VERSION 5.7 ;
  NOWIREEXTENSIONATPIN ON ;
  DIVIDERCHAR "/" ;
  BUSBITCHARS "[]" ;
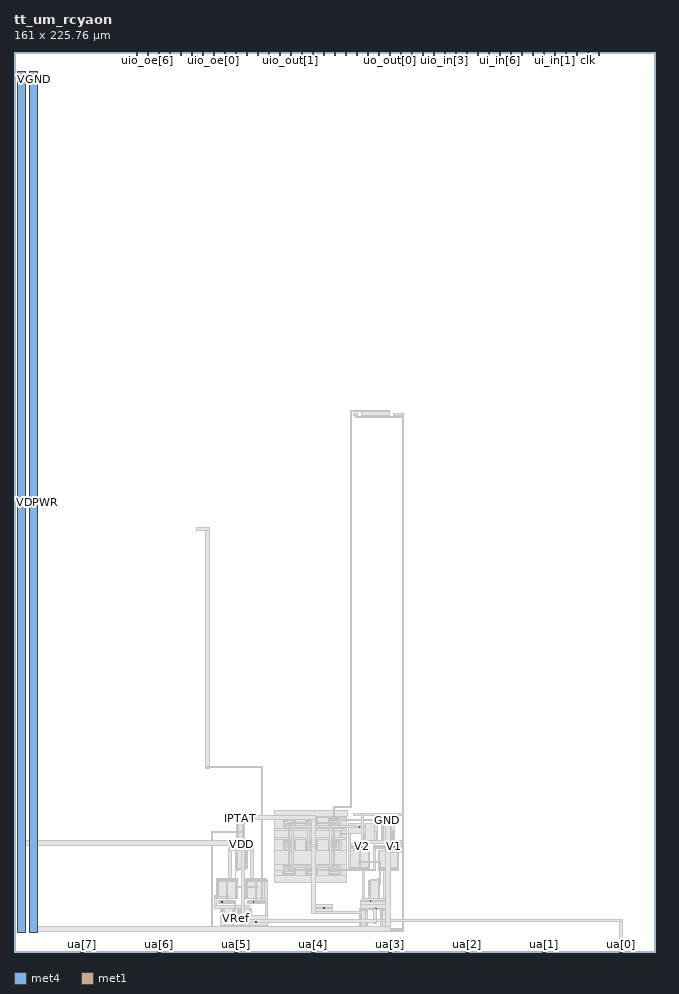
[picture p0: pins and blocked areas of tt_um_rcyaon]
MACRO tt_um_rcyaon
  CLASS BLOCK ;
  FOREIGN tt_um_rcyaon ;
  ORIGIN 0.000 0.000 ;
  SIZE 161.000 BY 225.760 ;
  PIN VGND
    USE GROUND ;
    PORT
      LAYER met4 ;
        RECT 4.000 5.000 6.000 220.760 ;
    END
  END VGND
  PIN VDPWR
    PORT
      LAYER met4 ;
        RECT 1.000 5.000 3.000 220.760 ;
    END
  END VDPWR
  PIN uo_out[7]
    PORT
      LAYER met4 ;
        RECT 74.830 224.760 75.130 225.760 ;
    END
  END uo_out[7]
  PIN uo_out[6]
    PORT
      LAYER met4 ;
        RECT 77.590 224.760 77.890 225.760 ;
    END
  END uo_out[6]
  PIN uo_out[5]
    PORT
      LAYER met4 ;
        RECT 80.350 224.760 80.650 225.760 ;
    END
  END uo_out[5]
  PIN uo_out[4]
    PORT
      LAYER met4 ;
        RECT 83.110 224.760 83.410 225.760 ;
    END
  END uo_out[4]
  PIN uo_out[3]
    PORT
      LAYER met4 ;
        RECT 85.870 224.760 86.170 225.760 ;
    END
  END uo_out[3]
  PIN uo_out[2]
    PORT
      LAYER met4 ;
        RECT 88.630 224.760 88.930 225.760 ;
    END
  END uo_out[2]
  PIN uo_out[1]
    PORT
      LAYER met4 ;
        RECT 91.390 224.760 91.690 225.760 ;
    END
  END uo_out[1]
  PIN uo_out[0]
    PORT
      LAYER met4 ;
        RECT 94.150 224.760 94.450 225.760 ;
    END
  END uo_out[0]
  PIN uio_out[7]
    PORT
      LAYER met4 ;
        RECT 52.750 224.760 53.050 225.760 ;
    END
  END uio_out[7]
  PIN uio_out[6]
    PORT
      LAYER met4 ;
        RECT 55.510 224.760 55.810 225.760 ;
    END
  END uio_out[6]
  PIN uio_out[5]
    PORT
      LAYER met4 ;
        RECT 58.270 224.760 58.570 225.760 ;
    END
  END uio_out[5]
  PIN uio_out[4]
    PORT
      LAYER met4 ;
        RECT 61.030 224.760 61.330 225.760 ;
    END
  END uio_out[4]
  PIN uio_out[3]
    PORT
      LAYER met4 ;
        RECT 63.790 224.760 64.090 225.760 ;
    END
  END uio_out[3]
  PIN uio_out[2]
    PORT
      LAYER met4 ;
        RECT 66.550 224.760 66.850 225.760 ;
    END
  END uio_out[2]
  PIN uio_out[1]
    PORT
      LAYER met4 ;
        RECT 69.310 224.760 69.610 225.760 ;
    END
  END uio_out[1]
  PIN uio_out[0]
    PORT
      LAYER met4 ;
        RECT 72.070 224.760 72.370 225.760 ;
    END
  END uio_out[0]
  PIN uio_oe[7]
    PORT
      LAYER met4 ;
        RECT 30.670 224.760 30.970 225.760 ;
    END
  END uio_oe[7]
  PIN uio_oe[6]
    PORT
      LAYER met4 ;
        RECT 33.430 224.760 33.730 225.760 ;
    END
  END uio_oe[6]
  PIN uio_oe[5]
    PORT
      LAYER met4 ;
        RECT 36.190 224.760 36.490 225.760 ;
    END
  END uio_oe[5]
  PIN uio_oe[4]
    PORT
      LAYER met4 ;
        RECT 38.950 224.760 39.250 225.760 ;
    END
  END uio_oe[4]
  PIN uio_oe[3]
    PORT
      LAYER met4 ;
        RECT 41.710 224.760 42.010 225.760 ;
    END
  END uio_oe[3]
  PIN uio_oe[2]
    PORT
      LAYER met4 ;
        RECT 44.470 224.760 44.770 225.760 ;
    END
  END uio_oe[2]
  PIN uio_oe[1]
    PORT
      LAYER met4 ;
        RECT 47.230 224.760 47.530 225.760 ;
    END
  END uio_oe[1]
  PIN uio_oe[0]
    PORT
      LAYER met4 ;
        RECT 49.990 224.760 50.290 225.760 ;
    END
  END uio_oe[0]
  PIN uio_in[7]
    PORT
      LAYER met4 ;
        RECT 96.910 224.760 97.210 225.760 ;
    END
  END uio_in[7]
  PIN uio_in[6]
    PORT
      LAYER met4 ;
        RECT 99.670 224.760 99.970 225.760 ;
    END
  END uio_in[6]
  PIN uio_in[5]
    PORT
      LAYER met4 ;
        RECT 102.430 224.760 102.730 225.760 ;
    END
  END uio_in[5]
  PIN uio_in[4]
    PORT
      LAYER met4 ;
        RECT 105.190 224.760 105.490 225.760 ;
    END
  END uio_in[4]
  PIN uio_in[3]
    PORT
      LAYER met4 ;
        RECT 107.950 224.760 108.250 225.760 ;
    END
  END uio_in[3]
  PIN uio_in[2]
    PORT
      LAYER met4 ;
        RECT 110.710 224.760 111.010 225.760 ;
    END
  END uio_in[2]
  PIN uio_in[1]
    PORT
      LAYER met4 ;
        RECT 113.470 224.760 113.770 225.760 ;
    END
  END uio_in[1]
  PIN uio_in[0]
    PORT
      LAYER met4 ;
        RECT 116.230 224.760 116.530 225.760 ;
    END
  END uio_in[0]
  PIN ui_in[7]
    PORT
      LAYER met4 ;
        RECT 118.990 224.760 119.290 225.760 ;
    END
  END ui_in[7]
  PIN ui_in[6]
    PORT
      LAYER met4 ;
        RECT 121.750 224.760 122.050 225.760 ;
    END
  END ui_in[6]
  PIN ui_in[5]
    PORT
      LAYER met4 ;
        RECT 124.510 224.760 124.810 225.760 ;
    END
  END ui_in[5]
  PIN ui_in[4]
    PORT
      LAYER met4 ;
        RECT 127.270 224.760 127.570 225.760 ;
    END
  END ui_in[4]
  PIN ui_in[3]
    PORT
      LAYER met4 ;
        RECT 130.030 224.760 130.330 225.760 ;
    END
  END ui_in[3]
  PIN ui_in[2]
    PORT
      LAYER met4 ;
        RECT 132.790 224.760 133.090 225.760 ;
    END
  END ui_in[2]
  PIN ui_in[1]
    PORT
      LAYER met4 ;
        RECT 135.550 224.760 135.850 225.760 ;
    END
  END ui_in[1]
  PIN ui_in[0]
    PORT
      LAYER met4 ;
        RECT 138.310 224.760 138.610 225.760 ;
    END
  END ui_in[0]
  PIN ua[7]
    PORT
      LAYER met4 ;
        RECT 16.570 0.000 17.470 1.000 ;
    END
  END ua[7]
  PIN ua[6]
    PORT
      LAYER met4 ;
        RECT 35.890 0.000 36.790 1.000 ;
    END
  END ua[6]
  PIN ua[5]
    PORT
      LAYER met4 ;
        RECT 55.210 0.000 56.110 1.000 ;
    END
  END ua[5]
  PIN ua[4]
    PORT
      LAYER met4 ;
        RECT 74.530 0.000 75.430 1.000 ;
    END
  END ua[4]
  PIN ua[3]
    PORT
      LAYER met4 ;
        RECT 93.850 0.000 94.750 1.000 ;
    END
  END ua[3]
  PIN ua[2]
    PORT
      LAYER met4 ;
        RECT 113.170 0.000 114.070 1.000 ;
    END
  END ua[2]
  PIN ua[1]
    PORT
      LAYER met4 ;
        RECT 132.490 0.000 133.390 1.000 ;
    END
  END ua[1]
  PIN ua[0]
    ANTENNAGATEAREA 16.000000 ;
    ANTENNADIFFAREA 3.180000 ;
    PORT
      LAYER met4 ;
        RECT 151.810 0.000 152.710 1.000 ;
    END
  END ua[0]
  PIN rst_n
    PORT
      LAYER met4 ;
        RECT 141.070 224.760 141.370 225.760 ;
    END
  END rst_n
  PIN ena
    PORT
      LAYER met4 ;
        RECT 146.590 224.760 146.890 225.760 ;
    END
  END ena
  PIN clk
    PORT
      LAYER met4 ;
        RECT 143.830 224.760 144.130 225.760 ;
    END
  END clk
  PIN IPTAT
    ANTENNAGATEAREA 4.000000 ;
    ANTENNADIFFAREA 1.522400 ;
    PORT
      LAYER met1 ;
        RECT 77.630 10.970 77.770 11.110 ;
    END
    PORT
      LAYER met1 ;
        RECT 56.745 33.310 56.885 33.450 ;
    END
  END IPTAT
  PIN GND
    ANTENNADIFFAREA 76.798798 ;
    PORT
      LAYER met1 ;
        RECT 93.515 32.945 93.655 33.085 ;
    END
    PORT
      LAYER met1 ;
        RECT 94.545 32.690 94.685 32.830 ;
    END
    PORT
      LAYER met1 ;
        RECT 53.980 5.875 54.120 6.015 ;
    END
    PORT
      LAYER met1 ;
        RECT 52.690 6.065 52.830 6.205 ;
    END
  END GND
  PIN VDD
    ANTENNADIFFAREA 13.678100 ;
    PORT
      LAYER met1 ;
        RECT 90.805 10.850 90.945 10.990 ;
    END
    PORT
      LAYER met1 ;
        RECT 89.390 12.765 89.505 12.860 ;
    END
    PORT
      LAYER met1 ;
        RECT 57.025 27.020 57.165 27.160 ;
    END
    PORT
      LAYER met1 ;
        RECT 57.870 26.035 57.985 26.130 ;
    END
  END VDD
  PIN V1
    ANTENNAGATEAREA 16.000000 ;
    ANTENNADIFFAREA 3.699200 ;
    PORT
      LAYER met1 ;
        RECT 95.125 26.315 95.355 26.560 ;
    END
    PORT
      LAYER met1 ;
        RECT 52.020 12.335 52.250 12.580 ;
    END
  END V1
  PIN V2
    ANTENNAGATEAREA 24.000000 ;
    ANTENNADIFFAREA 1.060000 ;
    PORT
      LAYER met1 ;
        RECT 87.185 26.310 87.325 26.450 ;
    END
    PORT
      LAYER met1 ;
        RECT 60.050 12.445 60.190 12.585 ;
    END
  END V2
  PIN Vout
    ANTENNAGATEAREA 54.022499 ;
    ANTENNADIFFAREA 6.561300 ;
    PORT
      LAYER met1 ;
        RECT 86.560 31.325 86.700 31.465 ;
    END
    PORT
      LAYER met1 ;
        RECT 60.675 7.430 60.815 7.570 ;
    END
  END Vout
  PIN VRef
    ANTENNAGATEAREA 16.000000 ;
    ANTENNADIFFAREA 3.180000 ;
    PORT
      LAYER met1 ;
        RECT 55.575 8.325 55.715 8.465 ;
    END
  END VRef
  OBS
      LAYER pwell ;
        RECT 65.675 34.245 66.355 34.795 ;
        RECT 67.510 34.350 82.215 35.315 ;
        RECT 67.510 34.245 83.340 34.350 ;
        RECT 65.675 33.485 83.340 34.245 ;
      LAYER nwell ;
        RECT 55.875 27.925 57.765 32.915 ;
      LAYER pwell ;
        RECT 65.675 31.035 67.845 33.485 ;
        RECT 70.295 31.035 73.385 33.485 ;
        RECT 75.835 31.035 79.050 33.485 ;
        RECT 81.500 31.035 83.340 33.485 ;
        RECT 65.675 30.275 83.340 31.035 ;
        RECT 65.675 28.745 66.355 30.275 ;
        RECT 67.470 28.745 83.340 30.275 ;
        RECT 65.675 27.985 83.340 28.745 ;
        RECT 87.895 28.015 91.245 32.275 ;
        RECT 92.205 28.015 95.555 32.275 ;
      LAYER nwell ;
        RECT 55.600 20.870 58.490 25.860 ;
      LAYER pwell ;
        RECT 65.675 25.535 67.845 27.985 ;
        RECT 70.295 25.535 73.370 27.985 ;
        RECT 75.820 25.535 79.050 27.985 ;
        RECT 81.500 25.535 83.340 27.985 ;
        RECT 65.675 25.080 83.340 25.535 ;
        RECT 65.675 24.775 71.055 25.080 ;
        RECT 65.675 22.635 66.355 24.775 ;
        RECT 67.470 23.995 71.055 24.775 ;
        RECT 72.610 23.995 76.580 25.080 ;
        RECT 78.290 23.995 83.340 25.080 ;
        RECT 67.470 23.315 83.340 23.995 ;
        RECT 67.470 22.635 71.055 23.315 ;
        RECT 65.675 22.345 71.055 22.635 ;
        RECT 72.625 22.345 76.595 23.315 ;
        RECT 78.290 22.345 83.340 23.315 ;
        RECT 65.675 21.875 83.340 22.345 ;
        RECT 65.675 19.425 67.845 21.875 ;
        RECT 70.295 19.425 73.385 21.875 ;
        RECT 75.835 19.425 79.050 21.875 ;
        RECT 81.500 19.425 83.340 21.875 ;
      LAYER nwell ;
        RECT 84.105 20.355 89.275 25.585 ;
        RECT 91.330 20.355 96.500 25.585 ;
      LAYER pwell ;
        RECT 65.675 19.030 83.340 19.425 ;
        RECT 67.085 18.665 83.340 19.030 ;
        RECT 67.510 18.585 83.340 18.665 ;
      LAYER nwell ;
        RECT 50.875 13.310 56.045 18.540 ;
        RECT 58.100 13.310 63.270 18.540 ;
      LAYER pwell ;
        RECT 67.510 17.655 82.215 18.585 ;
      LAYER nwell ;
        RECT 88.885 13.035 91.775 18.025 ;
      LAYER pwell ;
        RECT 51.820 6.620 55.170 10.880 ;
        RECT 56.130 6.620 59.480 10.880 ;
      LAYER nwell ;
        RECT 86.790 5.865 88.680 10.855 ;
        RECT 91.980 5.860 93.870 10.850 ;
      LAYER li1 ;
        RECT 85.365 134.910 86.055 134.960 ;
        RECT 87.345 134.910 88.035 134.960 ;
        RECT 89.340 134.910 90.030 134.960 ;
        RECT 91.380 134.910 92.070 134.960 ;
        RECT 93.390 134.910 94.080 134.960 ;
        RECT 95.365 134.930 96.055 134.960 ;
        RECT 95.345 134.910 96.055 134.930 ;
        RECT 85.265 134.740 86.155 134.910 ;
        RECT 87.245 134.740 88.135 134.910 ;
        RECT 89.240 134.740 90.130 134.910 ;
        RECT 91.280 134.740 92.170 134.910 ;
        RECT 93.290 134.740 94.180 134.910 ;
        RECT 95.265 134.740 96.155 134.910 ;
        RECT 85.365 134.660 86.055 134.740 ;
        RECT 87.345 134.660 88.035 134.740 ;
        RECT 89.340 134.660 90.030 134.740 ;
        RECT 91.380 134.660 92.070 134.740 ;
        RECT 93.390 134.660 94.080 134.740 ;
        RECT 95.345 134.660 96.055 134.740 ;
        RECT 85.675 134.565 85.845 134.660 ;
        RECT 87.520 134.620 87.690 134.660 ;
        RECT 89.620 134.620 89.790 134.660 ;
        RECT 91.620 134.620 91.790 134.660 ;
        RECT 93.620 134.620 93.790 134.660 ;
        RECT 95.345 134.600 95.515 134.660 ;
        RECT 46.305 106.285 46.475 106.295 ;
        RECT 45.925 106.235 46.615 106.285 ;
        RECT 45.825 106.065 46.715 106.235 ;
        RECT 45.925 105.985 46.615 106.065 ;
        RECT 46.305 105.965 46.475 105.985 ;
        RECT 48.475 46.355 48.645 46.435 ;
        RECT 48.210 46.305 48.900 46.355 ;
        RECT 48.110 46.135 49.000 46.305 ;
        RECT 48.210 46.055 48.900 46.135 ;
        RECT 67.640 34.810 67.810 35.140 ;
        RECT 68.440 34.810 68.610 35.140 ;
        RECT 69.250 34.810 69.420 35.140 ;
        RECT 70.260 34.810 70.430 35.140 ;
        RECT 71.060 34.810 71.230 35.140 ;
        RECT 71.870 34.810 72.040 35.140 ;
        RECT 72.665 34.810 72.835 35.140 ;
        RECT 73.465 34.810 73.635 35.140 ;
        RECT 74.275 34.810 74.445 35.140 ;
        RECT 75.075 34.810 75.245 35.140 ;
        RECT 75.875 34.810 76.045 35.140 ;
        RECT 76.675 34.810 76.845 35.140 ;
        RECT 77.590 34.810 77.760 35.140 ;
        RECT 78.715 34.810 78.885 35.140 ;
        RECT 79.515 34.810 79.685 35.140 ;
        RECT 80.315 34.810 80.485 35.140 ;
        RECT 81.115 34.810 81.285 35.140 ;
        RECT 81.915 34.810 82.085 35.140 ;
        RECT 85.365 34.740 86.055 34.820 ;
        RECT 87.345 34.740 88.035 34.820 ;
        RECT 89.340 34.740 90.030 34.820 ;
        RECT 91.380 34.740 92.070 34.820 ;
        RECT 93.390 34.740 94.080 34.820 ;
        RECT 95.365 34.740 96.055 34.820 ;
        RECT 65.850 34.495 66.180 34.665 ;
        RECT 85.265 34.570 86.155 34.740 ;
        RECT 87.245 34.570 88.135 34.740 ;
        RECT 89.240 34.570 90.130 34.740 ;
        RECT 91.280 34.570 92.170 34.740 ;
        RECT 93.290 34.570 94.180 34.740 ;
        RECT 95.265 34.570 96.155 34.740 ;
        RECT 85.365 34.520 86.055 34.570 ;
        RECT 87.345 34.520 88.035 34.570 ;
        RECT 89.340 34.520 90.030 34.570 ;
        RECT 91.380 34.520 92.070 34.570 ;
        RECT 93.390 34.520 94.080 34.570 ;
        RECT 95.365 34.520 96.055 34.570 ;
        RECT 85.540 34.355 85.710 34.520 ;
        RECT 87.365 34.250 87.535 34.520 ;
        RECT 89.580 34.345 89.750 34.520 ;
        RECT 91.670 34.350 91.840 34.520 ;
        RECT 93.600 34.350 93.770 34.520 ;
        RECT 95.635 34.320 95.805 34.520 ;
        RECT 65.850 33.695 66.180 33.865 ;
        RECT 67.215 33.615 68.205 34.115 ;
        RECT 69.935 33.615 70.925 34.115 ;
        RECT 71.640 33.845 71.970 34.015 ;
        RECT 56.320 32.945 57.320 33.175 ;
        RECT 65.850 32.895 66.180 33.065 ;
        RECT 56.095 28.735 56.265 32.735 ;
        RECT 57.375 28.735 57.545 32.735 ;
        RECT 65.850 32.075 66.180 32.245 ;
        RECT 65.850 31.275 66.180 31.445 ;
        RECT 67.215 30.905 67.715 33.615 ;
        RECT 68.025 31.575 68.385 33.305 ;
        RECT 68.730 31.920 69.410 32.600 ;
        RECT 69.755 31.575 70.115 33.305 ;
        RECT 68.025 31.215 70.115 31.575 ;
        RECT 70.425 30.905 70.925 33.615 ;
        RECT 72.755 33.615 73.745 34.115 ;
        RECT 75.475 33.615 76.465 34.115 ;
        RECT 77.250 33.845 77.580 34.015 ;
        RECT 71.640 33.000 71.970 33.170 ;
        RECT 71.640 32.200 71.970 32.370 ;
        RECT 71.640 31.400 71.970 31.570 ;
        RECT 65.850 30.475 66.180 30.645 ;
        RECT 67.215 30.405 68.205 30.905 ;
        RECT 69.935 30.405 70.925 30.905 ;
        RECT 72.755 30.905 73.255 33.615 ;
        RECT 73.565 31.575 73.925 33.305 ;
        RECT 74.270 31.920 74.950 32.600 ;
        RECT 75.295 31.575 75.655 33.305 ;
        RECT 73.565 31.215 75.655 31.575 ;
        RECT 75.965 30.905 76.465 33.615 ;
        RECT 78.420 33.615 79.410 34.115 ;
        RECT 81.140 33.615 82.130 34.115 ;
        RECT 82.835 34.050 83.165 34.220 ;
        RECT 77.250 33.000 77.580 33.170 ;
        RECT 77.250 32.200 77.580 32.370 ;
        RECT 77.250 31.400 77.580 31.570 ;
        RECT 71.640 30.600 71.970 30.770 ;
        RECT 72.755 30.405 73.745 30.905 ;
        RECT 75.475 30.405 76.465 30.905 ;
        RECT 78.420 30.905 78.920 33.615 ;
        RECT 79.230 31.575 79.590 33.305 ;
        RECT 79.935 31.920 80.615 32.600 ;
        RECT 80.960 31.575 81.320 33.305 ;
        RECT 79.230 31.215 81.320 31.575 ;
        RECT 81.630 30.905 82.130 33.615 ;
        RECT 82.835 33.250 83.165 33.420 ;
        RECT 82.835 32.450 83.165 32.620 ;
        RECT 82.835 31.630 83.165 31.800 ;
        RECT 77.250 30.600 77.580 30.770 ;
        RECT 78.420 30.405 79.410 30.905 ;
        RECT 81.140 30.405 82.130 30.905 ;
        RECT 82.835 30.830 83.165 31.000 ;
        RECT 82.835 29.965 83.165 30.135 ;
        RECT 65.850 29.625 66.180 29.795 ;
        RECT 67.600 29.425 67.770 29.755 ;
        RECT 68.420 29.425 68.590 29.755 ;
        RECT 69.220 29.425 69.390 29.755 ;
        RECT 70.020 29.425 70.190 29.755 ;
        RECT 70.840 29.425 71.010 29.755 ;
        RECT 71.800 29.425 71.970 29.755 ;
        RECT 72.665 29.425 72.835 29.755 ;
        RECT 73.465 29.425 73.635 29.755 ;
        RECT 74.275 29.425 74.445 29.755 ;
        RECT 75.075 29.425 75.245 29.755 ;
        RECT 75.875 29.425 76.045 29.755 ;
        RECT 76.675 29.425 76.845 29.755 ;
        RECT 77.590 29.425 77.760 29.755 ;
        RECT 78.715 29.425 78.885 29.755 ;
        RECT 79.515 29.425 79.685 29.755 ;
        RECT 80.315 29.425 80.485 29.755 ;
        RECT 81.115 29.425 81.285 29.755 ;
        RECT 81.915 29.425 82.085 29.755 ;
        RECT 82.835 29.090 83.165 29.260 ;
        RECT 65.850 28.735 66.180 28.905 ;
        RECT 56.065 28.115 57.575 28.385 ;
        RECT 67.215 28.115 68.205 28.615 ;
        RECT 69.935 28.115 70.925 28.615 ;
        RECT 71.640 28.455 71.970 28.625 ;
        RECT 65.850 27.925 66.180 28.095 ;
        RECT 65.850 27.125 66.180 27.295 ;
        RECT 65.850 26.325 66.180 26.495 ;
        RECT 55.790 25.400 58.300 25.670 ;
        RECT 65.850 25.525 66.180 25.695 ;
        RECT 67.215 25.405 67.715 28.115 ;
        RECT 68.025 26.075 68.385 27.805 ;
        RECT 68.730 26.420 69.410 27.100 ;
        RECT 69.755 26.075 70.115 27.805 ;
        RECT 68.025 25.715 70.115 26.075 ;
        RECT 70.425 25.405 70.925 28.115 ;
        RECT 72.740 28.115 73.730 28.615 ;
        RECT 75.460 28.115 76.450 28.615 ;
        RECT 77.195 28.455 77.525 28.625 ;
        RECT 71.640 27.610 71.970 27.780 ;
        RECT 71.640 26.810 71.970 26.980 ;
        RECT 71.640 26.010 71.970 26.180 ;
        RECT 55.820 21.050 55.990 25.050 ;
        RECT 58.100 21.050 58.270 25.050 ;
        RECT 67.215 24.905 68.205 25.405 ;
        RECT 69.935 24.905 70.925 25.405 ;
        RECT 72.740 25.405 73.240 28.115 ;
        RECT 73.550 26.075 73.910 27.805 ;
        RECT 74.255 26.420 74.935 27.100 ;
        RECT 75.280 26.075 75.640 27.805 ;
        RECT 73.550 25.715 75.640 26.075 ;
        RECT 75.950 25.405 76.450 28.115 ;
        RECT 78.420 28.115 79.410 28.615 ;
        RECT 81.140 28.115 82.130 28.615 ;
        RECT 82.835 28.290 83.165 28.460 ;
        RECT 88.065 28.145 88.235 32.145 ;
        RECT 90.345 28.145 90.515 32.145 ;
        RECT 90.835 28.145 91.105 32.145 ;
        RECT 92.375 28.145 92.545 32.145 ;
        RECT 94.655 28.145 94.825 32.145 ;
        RECT 95.145 28.145 95.415 32.145 ;
        RECT 77.195 27.610 77.525 27.780 ;
        RECT 77.195 26.810 77.525 26.980 ;
        RECT 77.195 26.010 77.525 26.180 ;
        RECT 71.640 25.210 71.970 25.380 ;
        RECT 72.740 24.905 73.730 25.405 ;
        RECT 75.460 24.905 76.450 25.405 ;
        RECT 78.420 25.405 78.920 28.115 ;
        RECT 79.230 26.075 79.590 27.805 ;
        RECT 79.935 26.420 80.615 27.100 ;
        RECT 80.960 26.075 81.320 27.805 ;
        RECT 79.230 25.715 81.320 26.075 ;
        RECT 81.630 25.405 82.130 28.115 ;
        RECT 88.290 27.705 90.290 27.935 ;
        RECT 92.600 27.705 94.600 27.935 ;
        RECT 82.835 27.480 83.165 27.650 ;
        RECT 82.835 26.680 83.165 26.850 ;
        RECT 82.835 25.880 83.165 26.050 ;
        RECT 84.550 26.015 88.830 26.245 ;
        RECT 91.775 26.015 96.055 26.245 ;
        RECT 77.195 25.210 77.525 25.380 ;
        RECT 78.420 24.905 79.410 25.405 ;
        RECT 81.140 24.905 82.130 25.405 ;
        RECT 82.835 25.080 83.165 25.250 ;
        RECT 65.850 24.715 66.180 24.885 ;
        RECT 82.835 24.270 83.165 24.440 ;
        RECT 65.850 23.985 66.180 24.155 ;
        RECT 67.600 23.490 67.770 23.820 ;
        RECT 68.420 23.490 68.590 23.820 ;
        RECT 69.220 23.490 69.390 23.820 ;
        RECT 70.020 23.490 70.190 23.820 ;
        RECT 70.840 23.490 71.010 23.820 ;
        RECT 71.800 23.490 71.970 23.820 ;
        RECT 72.665 23.490 72.835 23.820 ;
        RECT 73.465 23.490 73.635 23.820 ;
        RECT 74.275 23.490 74.445 23.820 ;
        RECT 75.075 23.490 75.245 23.820 ;
        RECT 75.875 23.490 76.045 23.820 ;
        RECT 76.675 23.490 76.845 23.820 ;
        RECT 77.590 23.490 77.760 23.820 ;
        RECT 78.715 23.490 78.885 23.820 ;
        RECT 79.515 23.490 79.685 23.820 ;
        RECT 80.315 23.490 80.485 23.820 ;
        RECT 81.115 23.490 81.285 23.820 ;
        RECT 81.915 23.490 82.085 23.820 ;
        RECT 82.835 23.305 83.165 23.475 ;
        RECT 65.850 23.065 66.180 23.235 ;
        RECT 82.835 22.600 83.165 22.770 ;
        RECT 65.850 22.360 66.180 22.530 ;
        RECT 67.215 22.005 68.205 22.505 ;
        RECT 69.935 22.005 70.925 22.505 ;
        RECT 71.635 22.045 71.965 22.215 ;
        RECT 65.850 21.560 66.180 21.730 ;
        RECT 56.045 20.610 58.045 20.840 ;
        RECT 65.850 20.760 66.180 20.930 ;
        RECT 65.850 19.960 66.180 20.130 ;
        RECT 65.850 19.160 66.180 19.330 ;
        RECT 67.215 19.295 67.715 22.005 ;
        RECT 68.025 19.965 68.385 21.695 ;
        RECT 68.730 20.310 69.410 20.990 ;
        RECT 69.755 19.965 70.115 21.695 ;
        RECT 68.025 19.605 70.115 19.965 ;
        RECT 70.425 19.295 70.925 22.005 ;
        RECT 72.755 22.005 73.745 22.505 ;
        RECT 75.475 22.005 76.465 22.505 ;
        RECT 77.195 22.045 77.525 22.215 ;
        RECT 71.635 21.245 71.965 21.415 ;
        RECT 71.635 20.445 71.965 20.615 ;
        RECT 71.635 19.645 71.965 19.815 ;
        RECT 67.215 18.795 68.205 19.295 ;
        RECT 69.935 18.795 70.925 19.295 ;
        RECT 72.755 19.295 73.255 22.005 ;
        RECT 73.565 19.965 73.925 21.695 ;
        RECT 74.270 20.310 74.950 20.990 ;
        RECT 75.295 19.965 75.655 21.695 ;
        RECT 73.565 19.605 75.655 19.965 ;
        RECT 75.965 19.295 76.465 22.005 ;
        RECT 78.420 22.005 79.410 22.505 ;
        RECT 81.140 22.005 82.130 22.505 ;
        RECT 77.195 21.245 77.525 21.415 ;
        RECT 77.195 20.445 77.525 20.615 ;
        RECT 77.195 19.645 77.525 19.815 ;
        RECT 71.635 18.845 71.965 19.015 ;
        RECT 72.755 18.795 73.745 19.295 ;
        RECT 75.475 18.795 76.465 19.295 ;
        RECT 78.420 19.295 78.920 22.005 ;
        RECT 79.230 19.965 79.590 21.695 ;
        RECT 79.935 20.310 80.615 20.990 ;
        RECT 80.960 19.965 81.320 21.695 ;
        RECT 79.230 19.605 81.320 19.965 ;
        RECT 81.630 19.295 82.130 22.005 ;
        RECT 82.835 21.915 83.165 22.085 ;
        RECT 84.325 21.405 84.495 25.405 ;
        RECT 86.605 21.405 86.775 25.405 ;
        RECT 88.885 21.405 89.055 25.405 ;
        RECT 91.550 21.405 91.720 25.405 ;
        RECT 93.830 21.405 94.000 25.405 ;
        RECT 96.110 21.405 96.280 25.405 ;
        RECT 82.835 21.115 83.165 21.285 ;
        RECT 84.295 20.545 89.085 20.815 ;
        RECT 91.520 20.545 96.310 20.815 ;
        RECT 82.835 20.315 83.165 20.485 ;
        RECT 82.835 19.515 83.165 19.685 ;
        RECT 77.195 18.845 77.525 19.015 ;
        RECT 78.420 18.795 79.410 19.295 ;
        RECT 81.140 18.795 82.130 19.295 ;
        RECT 82.835 18.715 83.165 18.885 ;
        RECT 51.065 18.080 55.855 18.350 ;
        RECT 58.290 18.080 63.080 18.350 ;
        RECT 67.640 17.830 67.810 18.160 ;
        RECT 68.440 17.830 68.610 18.160 ;
        RECT 69.250 17.830 69.420 18.160 ;
        RECT 70.260 17.830 70.430 18.160 ;
        RECT 71.060 17.830 71.230 18.160 ;
        RECT 71.870 17.830 72.040 18.160 ;
        RECT 72.665 17.830 72.835 18.160 ;
        RECT 73.465 17.830 73.635 18.160 ;
        RECT 74.275 17.830 74.445 18.160 ;
        RECT 75.075 17.830 75.245 18.160 ;
        RECT 75.875 17.830 76.045 18.160 ;
        RECT 76.675 17.830 76.845 18.160 ;
        RECT 77.590 17.830 77.760 18.160 ;
        RECT 78.715 17.830 78.885 18.160 ;
        RECT 79.515 17.830 79.685 18.160 ;
        RECT 80.315 17.830 80.485 18.160 ;
        RECT 81.115 17.830 81.285 18.160 ;
        RECT 81.915 17.830 82.085 18.160 ;
        RECT 89.330 18.055 91.330 18.285 ;
        RECT 51.095 13.490 51.265 17.490 ;
        RECT 53.375 13.490 53.545 17.490 ;
        RECT 55.655 13.490 55.825 17.490 ;
        RECT 58.320 13.490 58.490 17.490 ;
        RECT 60.600 13.490 60.770 17.490 ;
        RECT 62.880 13.490 63.050 17.490 ;
        RECT 89.105 13.845 89.275 17.845 ;
        RECT 91.385 13.845 91.555 17.845 ;
        RECT 89.075 13.225 91.585 13.495 ;
        RECT 51.320 12.650 55.600 12.880 ;
        RECT 58.545 12.650 62.825 12.880 ;
        RECT 52.775 10.960 54.775 11.190 ;
        RECT 57.085 10.960 59.085 11.190 ;
        RECT 51.960 6.750 52.230 10.750 ;
        RECT 52.550 6.750 52.720 10.750 ;
        RECT 54.830 6.750 55.000 10.750 ;
        RECT 56.270 6.750 56.540 10.750 ;
        RECT 56.860 6.750 57.030 10.750 ;
        RECT 59.140 6.750 59.310 10.750 ;
        RECT 86.980 10.395 88.490 10.665 ;
        RECT 92.170 10.390 93.680 10.660 ;
        RECT 45.925 6.065 46.615 6.145 ;
        RECT 48.210 6.135 48.900 6.215 ;
        RECT 45.825 5.895 46.715 6.065 ;
        RECT 48.110 5.965 49.000 6.135 ;
        RECT 87.010 6.045 87.180 10.045 ;
        RECT 88.290 6.045 88.460 10.045 ;
        RECT 92.200 6.040 92.370 10.040 ;
        RECT 93.480 6.040 93.650 10.040 ;
        RECT 48.210 5.915 48.900 5.965 ;
        RECT 45.925 5.845 46.615 5.895 ;
        RECT 46.425 5.775 46.595 5.845 ;
        RECT 48.690 5.750 48.860 5.915 ;
        RECT 87.235 5.605 88.235 5.835 ;
        RECT 92.425 5.600 93.425 5.830 ;
      LAYER met1 ;
        RECT 84.405 135.645 94.245 135.895 ;
        RECT 48.000 106.490 49.090 106.500 ;
        RECT 45.740 105.725 49.090 106.490 ;
        RECT 48.000 46.590 49.090 105.725 ;
        RECT 48.000 46.190 62.365 46.590 ;
        RECT 48.000 46.060 49.090 46.190 ;
        RECT 84.410 36.595 84.660 135.645 ;
        RECT 85.200 134.490 86.285 135.025 ;
        RECT 87.120 134.485 94.245 135.645 ;
        RECT 95.165 134.545 97.605 135.160 ;
        RECT 97.400 134.280 97.605 134.545 ;
        RECT 97.390 133.960 97.650 134.280 ;
        RECT 80.250 36.265 84.660 36.595 ;
        RECT 80.285 36.195 80.545 36.265 ;
        RECT 84.410 36.235 84.660 36.265 ;
        RECT 55.850 33.450 57.770 34.040 ;
        RECT 55.850 33.310 56.745 33.450 ;
        RECT 56.885 33.310 57.770 33.450 ;
        RECT 55.850 32.920 57.770 33.310 ;
        RECT 65.320 34.035 83.540 35.540 ;
        RECT 97.400 34.690 97.605 133.960 ;
        RECT 85.195 34.190 97.630 34.690 ;
        RECT 65.320 33.615 83.530 34.035 ;
        RECT 65.320 33.175 67.260 33.615 ;
        RECT 1.855 27.205 2.115 27.525 ;
        RECT 45.745 5.375 46.810 6.195 ;
        RECT 49.550 6.170 49.840 30.295 ;
        RECT 56.065 28.735 56.295 32.735 ;
        RECT 57.345 30.430 57.575 32.735 ;
        RECT 65.320 30.905 67.725 33.175 ;
        RECT 68.025 32.945 70.115 33.305 ;
        RECT 68.025 31.735 68.555 32.945 ;
        RECT 68.730 31.920 69.410 32.600 ;
        RECT 69.585 31.735 70.115 32.945 ;
        RECT 68.020 31.215 70.115 31.735 ;
        RECT 70.490 30.905 73.135 33.615 ;
        RECT 73.565 32.945 75.655 33.305 ;
        RECT 73.565 31.735 74.095 32.945 ;
        RECT 74.270 31.920 74.950 32.600 ;
        RECT 75.125 31.735 75.655 32.945 ;
        RECT 73.555 31.215 75.655 31.735 ;
        RECT 76.020 30.905 78.840 33.615 ;
        RECT 79.225 32.945 81.320 33.305 ;
        RECT 79.225 31.735 79.755 32.945 ;
        RECT 79.935 31.920 80.615 32.600 ;
        RECT 80.790 31.735 81.320 32.945 ;
        RECT 79.225 31.205 81.320 31.735 ;
        RECT 82.030 33.165 83.530 33.615 ;
        RECT 90.370 33.165 95.570 33.275 ;
        RECT 82.030 33.085 95.570 33.165 ;
        RECT 82.030 32.945 93.515 33.085 ;
        RECT 93.655 32.945 95.570 33.085 ;
        RECT 82.030 32.910 95.570 32.945 ;
        RECT 82.030 30.905 83.530 32.910 ;
        RECT 90.370 32.830 95.570 32.910 ;
        RECT 90.370 32.690 94.545 32.830 ;
        RECT 94.685 32.690 95.570 32.830 ;
        RECT 90.370 32.355 95.570 32.690 ;
        RECT 57.345 30.300 57.730 30.430 ;
        RECT 65.320 30.405 83.530 30.905 ;
        RECT 57.345 29.980 57.770 30.300 ;
        RECT 57.345 29.745 57.730 29.980 ;
        RECT 57.345 28.735 57.575 29.745 ;
        RECT 56.095 28.505 56.295 28.735 ;
        RECT 65.320 28.615 81.730 30.405 ;
        RECT 82.030 29.735 83.530 30.405 ;
        RECT 81.885 29.445 83.530 29.735 ;
        RECT 82.030 28.615 83.530 29.445 ;
        RECT 55.865 27.160 57.765 28.505 ;
        RECT 55.865 27.020 57.025 27.160 ;
        RECT 57.165 27.020 57.765 27.160 ;
        RECT 55.865 26.315 57.765 27.020 ;
        RECT 65.320 28.115 83.530 28.615 ;
        RECT 53.930 26.130 60.020 26.315 ;
        RECT 53.930 26.035 57.870 26.130 ;
        RECT 57.985 26.035 60.020 26.130 ;
        RECT 53.930 25.400 60.020 26.035 ;
        RECT 65.320 25.410 67.725 28.115 ;
        RECT 68.025 27.445 70.115 27.805 ;
        RECT 68.025 26.230 68.555 27.445 ;
        RECT 68.730 26.420 69.410 27.100 ;
        RECT 69.585 26.230 70.115 27.445 ;
        RECT 68.020 25.710 70.115 26.230 ;
        RECT 70.490 25.410 73.135 28.115 ;
        RECT 73.545 27.445 75.640 27.805 ;
        RECT 73.545 26.230 74.075 27.445 ;
        RECT 74.255 26.420 74.935 27.100 ;
        RECT 75.110 26.230 75.640 27.445 ;
        RECT 73.545 25.715 75.650 26.230 ;
        RECT 73.555 25.710 75.650 25.715 ;
        RECT 76.020 25.410 78.840 28.115 ;
        RECT 79.230 27.445 81.320 27.805 ;
        RECT 79.230 26.230 79.760 27.445 ;
        RECT 79.935 26.420 80.615 27.100 ;
        RECT 80.790 26.230 81.320 27.445 ;
        RECT 79.225 25.710 81.320 26.230 ;
        RECT 82.030 25.410 83.530 28.115 ;
        RECT 53.930 18.350 54.595 25.400 ;
        RECT 55.865 25.345 57.765 25.400 ;
        RECT 55.790 21.970 56.020 25.050 ;
        RECT 58.060 24.820 58.335 25.400 ;
        RECT 55.445 21.050 56.020 21.970 ;
        RECT 58.070 21.050 58.300 24.820 ;
        RECT 55.445 20.880 55.990 21.050 ;
        RECT 55.445 20.860 56.290 20.880 ;
        RECT 55.445 20.590 58.045 20.860 ;
        RECT 55.445 20.545 56.290 20.590 ;
        RECT 59.330 18.350 59.995 25.400 ;
        RECT 65.320 22.005 83.530 25.410 ;
        RECT 65.320 20.355 67.725 22.005 ;
        RECT 68.025 21.335 70.115 21.695 ;
        RECT 65.320 19.295 67.260 20.355 ;
        RECT 68.025 20.125 68.555 21.335 ;
        RECT 68.730 20.310 69.410 20.990 ;
        RECT 69.585 20.125 70.115 21.335 ;
        RECT 68.020 19.605 70.115 20.125 ;
        RECT 70.490 19.295 73.135 22.005 ;
        RECT 73.565 21.335 75.655 21.695 ;
        RECT 73.565 20.125 74.095 21.335 ;
        RECT 74.270 20.310 74.950 20.990 ;
        RECT 75.125 20.125 75.655 21.335 ;
        RECT 73.555 19.605 75.655 20.125 ;
        RECT 76.020 19.295 78.840 22.005 ;
        RECT 79.230 21.335 81.325 21.695 ;
        RECT 79.230 20.125 79.760 21.335 ;
        RECT 79.935 20.310 80.615 20.990 ;
        RECT 80.795 20.125 81.325 21.335 ;
        RECT 79.225 19.605 81.325 20.125 ;
        RECT 82.030 19.295 83.530 22.005 ;
        RECT 83.815 32.145 88.195 32.275 ;
        RECT 90.370 32.145 91.235 32.355 ;
        RECT 94.670 32.145 95.570 32.355 ;
        RECT 83.815 31.465 88.265 32.145 ;
        RECT 83.815 31.325 86.560 31.465 ;
        RECT 86.700 31.325 88.265 31.465 ;
        RECT 83.815 29.760 88.265 31.325 ;
        RECT 83.815 25.405 84.390 29.760 ;
        RECT 88.035 28.145 88.265 29.760 ;
        RECT 90.315 30.270 91.235 32.145 ;
        RECT 90.315 28.145 90.545 30.270 ;
        RECT 90.835 28.145 91.105 30.270 ;
        RECT 92.345 29.965 92.575 32.145 ;
        RECT 94.625 30.410 95.570 32.145 ;
        RECT 92.330 27.955 92.615 29.965 ;
        RECT 94.625 28.145 94.855 30.410 ;
        RECT 95.145 28.145 95.415 30.410 ;
        RECT 88.290 27.950 90.290 27.955 ;
        RECT 92.330 27.950 94.600 27.955 ;
        RECT 88.280 27.280 97.205 27.950 ;
        RECT 84.585 26.665 88.795 27.105 ;
        RECT 84.570 26.450 88.810 26.665 ;
        RECT 91.805 26.655 96.045 26.665 ;
        RECT 84.570 26.310 87.185 26.450 ;
        RECT 87.325 26.310 88.810 26.450 ;
        RECT 84.570 26.265 88.810 26.310 ;
        RECT 90.210 26.560 96.045 26.655 ;
        RECT 90.210 26.315 95.125 26.560 ;
        RECT 95.355 26.315 96.045 26.560 ;
        RECT 90.210 26.265 96.045 26.315 ;
        RECT 84.550 25.995 88.830 26.265 ;
        RECT 90.210 26.070 96.055 26.265 ;
        RECT 83.815 21.235 84.525 25.405 ;
        RECT 86.575 22.740 86.805 25.805 ;
        RECT 86.395 22.380 86.970 22.740 ;
        RECT 86.575 21.405 86.805 22.380 ;
        RECT 88.855 21.235 89.085 25.405 ;
        RECT 83.815 21.055 89.085 21.235 ;
        RECT 84.295 21.005 89.085 21.055 ;
        RECT 84.295 20.545 89.085 20.815 ;
        RECT 51.065 18.080 55.855 18.350 ;
        RECT 58.290 18.080 63.080 18.350 ;
        RECT 51.065 17.660 55.855 17.890 ;
        RECT 50.170 11.615 50.815 14.050 ;
        RECT 51.065 13.490 51.295 17.660 ;
        RECT 53.345 14.260 53.575 17.490 ;
        RECT 55.625 16.515 55.855 17.660 ;
        RECT 58.290 17.840 63.080 17.890 ;
        RECT 58.290 17.660 63.560 17.840 ;
        RECT 55.440 16.155 56.015 16.515 ;
        RECT 53.185 13.665 53.760 14.260 ;
        RECT 53.345 13.090 53.575 13.665 ;
        RECT 55.625 13.490 55.855 16.155 ;
        RECT 58.290 13.490 58.520 17.660 ;
        RECT 60.570 16.515 60.800 17.490 ;
        RECT 60.405 16.155 60.980 16.515 ;
        RECT 60.570 13.090 60.800 16.155 ;
        RECT 62.850 13.490 63.560 17.660 ;
        RECT 65.320 17.415 83.530 19.295 ;
        RECT 65.320 17.405 67.260 17.415 ;
        RECT 82.030 17.395 83.530 17.415 ;
        RECT 87.380 13.495 88.045 20.545 ;
        RECT 90.210 20.475 90.575 26.070 ;
        RECT 91.775 25.995 96.055 26.070 ;
        RECT 91.520 22.740 91.750 25.405 ;
        RECT 93.800 25.230 94.030 25.805 ;
        RECT 93.615 24.635 94.190 25.230 ;
        RECT 91.360 22.380 91.935 22.740 ;
        RECT 91.520 21.235 91.750 22.380 ;
        RECT 93.800 21.405 94.030 24.635 ;
        RECT 96.080 21.235 96.310 25.405 ;
        RECT 96.560 24.845 97.205 27.280 ;
        RECT 91.520 21.005 96.310 21.235 ;
        RECT 91.520 20.545 96.310 20.815 ;
        RECT 91.085 18.305 91.930 18.350 ;
        RECT 89.330 18.035 91.930 18.305 ;
        RECT 91.085 18.015 91.930 18.035 ;
        RECT 91.385 17.845 91.930 18.015 ;
        RECT 89.075 14.075 89.305 17.845 ;
        RECT 91.355 16.925 91.930 17.845 ;
        RECT 89.040 13.495 89.315 14.075 ;
        RECT 91.355 13.845 91.585 16.925 ;
        RECT 92.780 13.495 93.445 20.545 ;
        RECT 51.320 12.630 55.600 12.900 ;
        RECT 58.545 12.630 62.825 12.900 ;
        RECT 51.330 12.580 55.570 12.630 ;
        RECT 51.330 12.335 52.020 12.580 ;
        RECT 52.250 12.335 55.570 12.580 ;
        RECT 51.330 12.230 55.570 12.335 ;
        RECT 58.565 12.585 62.805 12.630 ;
        RECT 58.565 12.445 60.050 12.585 ;
        RECT 60.190 12.445 62.805 12.585 ;
        RECT 58.565 12.230 62.805 12.445 ;
        RECT 50.170 10.945 59.095 11.615 ;
        RECT 52.775 10.940 55.045 10.945 ;
        RECT 57.085 10.940 59.085 10.945 ;
        RECT 51.960 8.485 52.230 10.750 ;
        RECT 52.520 8.485 52.750 10.750 ;
        RECT 54.760 8.930 55.045 10.940 ;
        RECT 48.005 5.720 49.840 6.170 ;
        RECT 51.805 6.750 52.750 8.485 ;
        RECT 54.800 6.750 55.030 8.930 ;
        RECT 55.350 8.465 55.890 9.130 ;
        RECT 56.270 8.625 56.540 10.750 ;
        RECT 56.830 8.625 57.060 10.750 ;
        RECT 55.350 8.325 55.575 8.465 ;
        RECT 55.715 8.325 55.890 8.465 ;
        RECT 55.350 7.445 55.890 8.325 ;
        RECT 56.140 6.750 57.060 8.625 ;
        RECT 59.110 9.135 59.340 10.750 ;
        RECT 62.985 9.135 63.560 13.490 ;
        RECT 87.355 12.910 93.445 13.495 ;
        RECT 86.825 12.860 93.860 12.910 ;
        RECT 86.825 12.765 89.390 12.860 ;
        RECT 89.505 12.765 93.860 12.860 ;
        RECT 74.595 11.110 79.920 11.800 ;
        RECT 74.595 10.970 77.630 11.110 ;
        RECT 77.770 10.970 79.920 11.110 ;
        RECT 74.595 9.640 79.920 10.970 ;
        RECT 86.825 11.790 93.860 12.765 ;
        RECT 86.825 10.990 93.895 11.790 ;
        RECT 86.825 10.850 90.805 10.990 ;
        RECT 90.945 10.850 93.895 10.990 ;
        RECT 86.825 10.545 93.895 10.850 ;
        RECT 86.980 10.395 88.740 10.545 ;
        RECT 86.820 10.050 87.175 10.170 ;
        RECT 86.810 10.045 87.175 10.050 ;
        RECT 88.340 10.045 88.740 10.395 ;
        RECT 92.170 10.390 93.895 10.545 ;
        RECT 86.810 9.730 87.210 10.045 ;
        RECT 86.820 9.320 87.210 9.730 ;
        RECT 59.110 7.570 63.560 9.135 ;
        RECT 59.110 7.430 60.675 7.570 ;
        RECT 60.815 7.430 63.560 7.570 ;
        RECT 59.110 6.750 63.560 7.430 ;
        RECT 51.805 6.540 52.705 6.750 ;
        RECT 56.140 6.540 57.005 6.750 ;
        RECT 59.180 6.620 63.560 6.750 ;
        RECT 51.805 6.460 57.005 6.540 ;
        RECT 51.805 6.205 57.010 6.460 ;
        RECT 51.805 6.065 52.690 6.205 ;
        RECT 52.830 6.065 57.010 6.205 ;
        RECT 51.805 6.015 57.010 6.065 ;
        RECT 86.980 6.045 87.210 9.320 ;
        RECT 88.260 7.930 88.740 10.045 ;
        RECT 93.495 10.040 93.895 10.390 ;
        RECT 92.170 8.225 92.400 10.040 ;
        RECT 88.260 6.045 88.490 7.930 ;
        RECT 51.805 5.875 53.980 6.015 ;
        RECT 54.120 5.875 57.010 6.015 ;
        RECT 48.005 5.715 49.815 5.720 ;
        RECT 51.805 5.620 57.010 5.875 ;
        RECT 91.880 6.040 92.400 8.225 ;
        RECT 93.450 8.295 93.895 10.040 ;
        RECT 93.450 6.040 93.680 8.295 ;
        RECT 87.235 5.825 88.235 5.855 ;
        RECT 91.880 5.825 92.250 6.040 ;
        RECT 92.425 5.825 93.425 5.850 ;
        RECT 97.400 5.825 97.605 34.190 ;
        RECT 51.865 5.375 57.010 5.620 ;
        RECT 45.745 5.130 57.010 5.375 ;
        RECT 87.175 5.655 97.610 5.825 ;
        RECT 87.175 5.335 97.620 5.655 ;
        RECT 87.175 5.175 97.610 5.335 ;
        RECT 97.400 5.145 97.605 5.175 ;
        RECT 45.745 5.120 56.990 5.130 ;
        RECT 45.745 5.085 46.810 5.120 ;
      LAYER met2 ;
        RECT 85.200 134.480 86.290 135.025 ;
        RECT 85.590 134.235 85.900 134.480 ;
        RECT 97.390 134.235 97.650 134.280 ;
        RECT 85.580 134.015 97.650 134.235 ;
        RECT 85.590 134.010 85.900 134.015 ;
        RECT 97.390 133.960 97.650 134.015 ;
        RECT 57.080 33.490 57.360 33.860 ;
        RECT 57.510 30.270 57.770 30.300 ;
        RECT 49.510 29.980 57.770 30.270 ;
        RECT 49.510 29.895 57.720 29.980 ;
        RECT 49.570 29.890 49.830 29.895 ;
        RECT 1.845 27.180 2.125 27.550 ;
        RECT 56.835 27.225 57.115 27.595 ;
        RECT 55.445 21.640 55.600 21.970 ;
        RECT 55.445 21.320 55.775 21.640 ;
        RECT 55.445 16.495 55.600 21.320 ;
        RECT 55.445 16.380 55.765 16.495 ;
        RECT 60.515 16.380 60.775 16.475 ;
        RECT 55.445 16.235 60.835 16.380 ;
        RECT 55.445 16.175 55.765 16.235 ;
        RECT 55.445 16.170 55.600 16.175 ;
        RECT 60.515 16.155 60.775 16.235 ;
        RECT 53.390 14.045 53.650 14.160 ;
        RECT 50.170 13.900 53.760 14.045 ;
        RECT 50.350 13.685 50.610 13.900 ;
        RECT 53.390 13.840 53.650 13.900 ;
        RECT 52.590 12.410 55.560 12.555 ;
        RECT 55.300 12.235 55.560 12.410 ;
        RECT 62.040 12.400 62.390 46.620 ;
        RECT 80.260 36.515 80.445 36.590 ;
        RECT 80.260 36.195 80.545 36.515 ;
        RECT 74.515 32.390 74.775 32.440 ;
        RECT 80.260 32.390 80.445 36.195 ;
        RECT 68.970 32.365 80.445 32.390 ;
        RECT 68.965 32.235 80.445 32.365 ;
        RECT 68.965 32.070 69.230 32.235 ;
        RECT 74.515 32.120 74.775 32.235 ;
        RECT 68.965 26.910 69.140 32.070 ;
        RECT 80.160 31.945 80.445 32.235 ;
        RECT 69.585 31.750 70.125 31.785 ;
        RECT 69.585 31.735 79.690 31.750 ;
        RECT 69.585 31.200 79.720 31.735 ;
        RECT 68.945 26.590 69.205 26.910 ;
        RECT 68.965 20.870 69.140 26.590 ;
        RECT 69.585 21.700 70.125 31.200 ;
        RECT 73.570 27.375 74.075 31.200 ;
        RECT 74.480 26.550 74.760 26.920 ;
        RECT 79.215 21.700 79.720 31.200 ;
        RECT 80.260 26.940 80.445 31.945 ;
        RECT 85.420 31.280 85.700 31.650 ;
        RECT 80.155 26.620 80.445 26.940 ;
        RECT 87.265 26.695 87.615 34.630 ;
        RECT 93.830 32.510 94.110 32.880 ;
        RECT 69.585 21.240 79.740 21.700 ;
        RECT 69.585 21.225 70.125 21.240 ;
        RECT 68.950 20.685 69.210 20.870 ;
        RECT 80.260 20.820 80.445 26.620 ;
        RECT 91.975 26.245 92.235 26.565 ;
        RECT 93.725 24.995 93.985 25.055 ;
        RECT 96.765 24.995 97.025 25.210 ;
        RECT 93.615 24.850 97.205 24.995 ;
        RECT 93.725 24.735 93.985 24.850 ;
        RECT 86.600 22.660 86.860 22.740 ;
        RECT 91.775 22.720 91.930 22.725 ;
        RECT 91.610 22.660 91.930 22.720 ;
        RECT 86.540 22.515 91.930 22.660 ;
        RECT 86.600 22.420 86.860 22.515 ;
        RECT 91.610 22.400 91.930 22.515 ;
        RECT 74.475 20.685 74.735 20.750 ;
        RECT 80.185 20.685 80.445 20.820 ;
        RECT 90.265 20.685 90.525 20.820 ;
        RECT 68.950 20.550 90.560 20.685 ;
        RECT 68.960 20.520 90.560 20.550 ;
        RECT 74.475 20.430 74.735 20.520 ;
        RECT 80.185 20.500 80.445 20.520 ;
        RECT 90.265 20.500 90.525 20.520 ;
        RECT 91.775 17.575 91.930 22.400 ;
        RECT 91.600 17.255 91.930 17.575 ;
        RECT 91.775 16.925 91.930 17.255 ;
        RECT 62.085 12.350 62.345 12.400 ;
        RECT 55.350 8.040 55.520 12.235 ;
        RECT 90.530 10.705 90.810 11.075 ;
        RECT 74.910 10.070 87.100 10.120 ;
        RECT 74.790 9.700 87.100 10.070 ;
        RECT 74.910 9.680 87.100 9.700 ;
        RECT 55.350 7.630 152.715 8.040 ;
        RECT 55.350 7.455 59.955 7.630 ;
        RECT 55.350 7.450 55.520 7.455 ;
        RECT 59.695 7.415 59.955 7.455 ;
        RECT 46.380 5.780 46.640 6.100 ;
        RECT 53.290 5.675 53.570 6.045 ;
        RECT 97.360 5.335 97.620 5.655 ;
        RECT 151.820 0.555 152.715 7.630 ;
      LAYER met3 ;
        RECT 55.770 33.215 75.620 34.180 ;
        RECT 57.015 27.860 57.740 27.880 ;
        RECT 1.565 26.705 57.755 27.860 ;
        RECT 74.590 26.900 75.620 33.215 ;
        RECT 93.805 32.320 94.135 33.070 ;
        RECT 79.200 31.215 85.855 31.720 ;
        RECT 57.015 8.045 57.740 26.705 ;
        RECT 74.455 26.570 75.620 26.900 ;
        RECT 74.590 9.645 75.620 26.570 ;
        RECT 74.590 9.640 75.275 9.645 ;
        RECT 90.285 8.045 91.035 11.140 ;
        RECT 57.015 7.310 91.035 8.045 ;
        RECT 90.285 7.265 91.035 7.310 ;
        RECT 53.265 5.485 53.595 6.235 ;
        RECT 152.075 0.385 152.405 1.135 ;
      LAYER met4 ;
        RECT 93.115 6.410 94.380 33.270 ;
        RECT 6.000 5.190 94.380 6.410 ;
        RECT 6.000 5.120 94.315 5.190 ;
  END
END tt_um_rcyaon
END LIBRARY

